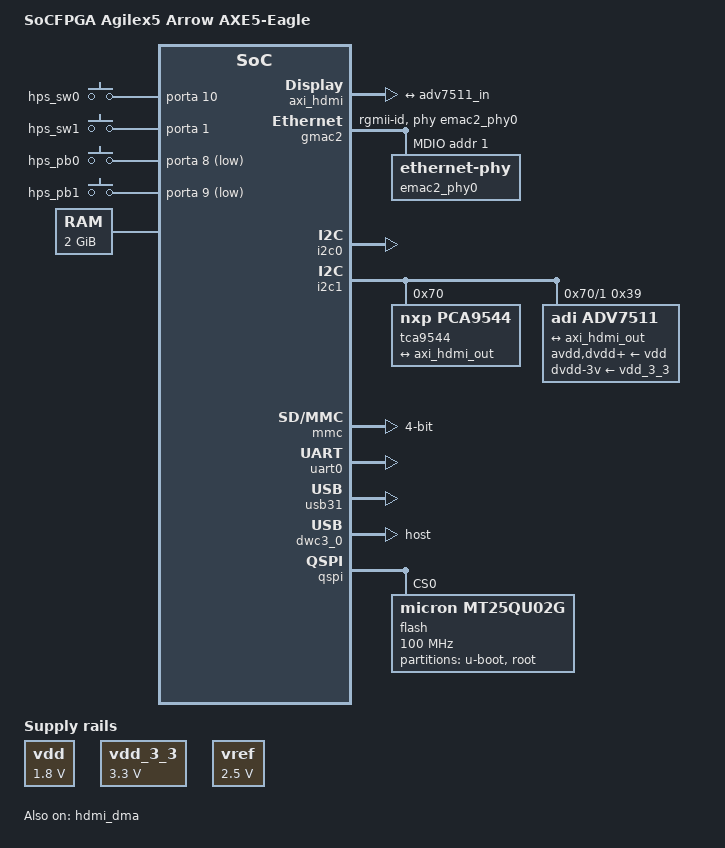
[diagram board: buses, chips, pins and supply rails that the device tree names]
// SPDX-License-Identifier:     GPL-2.0
/*
 * Copyright (C) 2024, Arrow Electronics, Inc.
 */
#include "../intel/socfpga_agilex5.dtsi"


/ {
	model = "SoCFPGA Agilex5 Arrow AXE5-Eagle";
	compatible = "intel,socfpga-agilex5-socdk", "intel,socfpga-agilex";

	aliases {
		serial0 = &uart0;
		ethernet0 = &gmac0;
		ethernet2 = &gmac2;
	};

	chosen {
		stdout-path = "serial0:115200n8";
		bootargs = "console=uart8250,mmio32,0x10c02000,115200n8 \
			root=/dev/ram0 rw initrd=0x10000000 init=/sbin/init \
			ramdisk_size=10000000 earlycon=uart8250,mmio32,0x10c02000,115200n8 \
			panic=-1 nosmp rootfstype=ext3";
	};

	/*leds {
		compatible = "gpio-leds";
		
		hps0 {
			label = "hps_led0";
			gpios = <&porta 6 GPIO_ACTIVE_HIGH>;
		};		

		hps1 {
			label = "hps_led1";
			gpios = <&porta 7 GPIO_ACTIVE_HIGH>;
		};
		
		fpga0_led_red {
			label = "fpga_led0_red";
			gpios = <&led_pio0 2 1>;
		};
		
		fpga0_led_green {
			label = "fpga_led0_green";
			gpios = <&led_pio0 1 1>;
		};	
		
		fpga0_led_blue {
			label = "fpga_led0_blue";
			gpios = <&led_pio0 0 1>;
		};
		
		fpga1_led_red {
			label = "fpga_led1_red";
			gpios = <&led_pio1 2 1>;
		};
		
		fpga1_led_green {
			label = "fpga_led1_green";
			gpios = <&led_pio1 1 1>;
		};	
		
		fpga1_led_blue {
			label = "fpga_led1_blue";
			gpios = <&led_pio1 0 1>;
		};
		
		fpga2_led_red {
			label = "fpga_led2_red";
			gpios = <&led_pio2 2 1>;
		};
		
		fpga2_led_green {
			label = "fpga_led2_green";
			gpios = <&led_pio2 1 1>;
		};	
		
		fpga2_led_blue {
			label = "fpga_led2_blue";
			gpios = <&led_pio2 0 1>;
		};
		
		fpga3_led_red {
			label = "fpga_led3_red";
			gpios = <&led_pio3 2 1>;
		};
		
		fpga3_led_green {
			label = "fpga_led3_green";
			gpios = <&led_pio3 1 1>;
		};	
		
		fpga3_led_blue {
			label = "fpga_led3_blue";
			gpios = <&led_pio3 0 1>;
		};									

	}; */
	
	gpio-keys {
		compatible = "gpio-keys";

		hps_sw0 {
			label = "hps_sw0";
			gpios = <&porta 10 0>;	
			linux,input-type = <5>;	/* EV_SW */
			linux,code = <0x0>;		
		};
		
		hps_sw1 {
			label = "hps_sw1";
			gpios = <&porta 1 0>;	
			linux,input-type = <5>;	/* EV_SW */
			linux,code = <0x0>;		
		};
		
		hps_pb0 {
			label = "hps_pb0";
			gpios = <&porta 8 1>;	
			linux,code = <187>;		/* KEY_F17 */
		};

		hps_pb1 {
			label = "hps_pb1";
			gpios = <&porta 9 1>;	
			linux,code = <188>;		/* KEY_F18 */
		};		
	};					

	memory {
		device_type = "memory";
		reg = <0x0 0x80000000 0x0 0x80000000>;
		#address-cells = <0x2>;
		#size-cells = <0x2>;
		u-boot,dm-pre-reloc;
	};
	
	dma_clk: dma_clk {
		#clock-cells = <0x0>;
		compatible = "fixed-clock";
		clock-frequency = <250000000>;
		clock-output-names = "dma_clock";
	};	
	
	hdmi_pll: hdmi_pll {
		compatible = "altr,altera_iopll-18.1";
		#clock-cells = <1>;
			hdmi_pll_outclk0: hdmi_pll_outclk0 {
			compatible = "fixed-clock";
			#clock-cells = <0>;
			clock-frequency = <148437500>;
			clock-output-names = "hdmi_pll-outclk0";
		}; 
	};
	
        vdd: regulator-vdd {
                compatible = "regulator-fixed";
                regulator-name = "fixed-supply";
                regulator-min-microvolt = <1800000>;
                regulator-max-microvolt = <1800000>;
                regulator-always-on;
        };

        vdd_3_3: regulator-vdd {
                compatible = "regulator-fixed";
                regulator-name = "fixed-supply";
                regulator-min-microvolt = <3300000>;
                regulator-max-microvolt = <3300000>;
                regulator-always-on;
        };

        vref: regulator-vref {
                compatible = "regulator-fixed";
                regulator-name = "fixed-supply";
                regulator-min-microvolt = <2500000>;
                regulator-max-microvolt = <2500000>;
                regulator-always-on;
        };		
	
	soc {
		sys_hps_bridges: bridge@20000000 {
			compatible = "simple-bus";
			reg = <0x20000000 0x20000000>;
			reg-names = "axi_h2f_lw";
			#address-cells = <2>;
			#size-cells = <1>;
			ranges = <0x00000001 0x08000000 0x28000000 0x00000008>,
				 <0x00000001 0x08000010 0x28000010 0x00000010>,
	  			 <0x00000001 0x08000020 0x28000020 0x00000010>,
	  			 <0x00000001 0x08000030 0x28000030 0x00000010>,
	  			 <0x00000001 0x08000040 0x28000040 0x00000010>,
	  			 <0x00000001 0x08000050 0x28000050 0x00000010>,
	  			 <0x00000001 0x08000060 0x28000060 0x00000010>,
				 <0x00000001 0x10000000 0x30000000 0x00010000>,
				 <0x00000001 0x10010000 0x30010000 0x00000800>;
				 
			sys_id: sys-id@108000000 {
				compatible = "altr,sysid-1.0";
				reg = <0x00000001 0x08000000 0x08>;
			};				 
				 
			/* pio device tree entry. for additional information see /linux/Documentation/devicetree/bindings/gpio/gpio-altera.txt */

			button_pio: button-pio@108000010 {
				compatible = "altr,pio-1.0";
				reg = <0x00000001 0x08000010 0x10>;
				interrupt-parent = <&intc>;
				interrupts = <0 20 4>;
				altr,ngpio = <2>;
				#gpio-cells = <2>;
				gpio-controller;
				interrupt-cells = <1>;
				interrupt-controller;
				altr,interrupt-type = <IRQ_TYPE_EDGE_FALLING>;
			};

			dipsw_pio: button-pio@108000020 {
				compatible = "altr,pio-1.0";
				reg = <0x00000001 0x08000020 0x10>;
				interrupt-parent = <&intc>;
				interrupts = <0 18 4>;
				altr,ngpio = <2>;
				#gpio-cells = <2>;
				gpio-controller;
				interrupt-cells = <1>;
				interrupt-controller;
				altr,interrupt-type = <IRQ_TYPE_EDGE_BOTH>;
			};

			led_pio0: led-pio0@108000030 {
				compatible = "altr,pio-1.0";
				reg = <0x00000001 0x08000030 0x10>;
				altr,ngpio = <3>;
				#gpio-cells = <2>;
				gpio-controller;
			};
			
			led_pio1: led-pio1@108000040 {
				compatible = "altr,pio-1.0";
				reg = <0x00000001 0x08000040 0x10>;
				altr,ngpio = <3>;
				#gpio-cells = <2>;
				gpio-controller;
			};
			
			led_pio2: led-pio2@108000050 {
				compatible = "altr,pio-1.0";
				reg = <0x00000001 0x01000050 0x10>;
				altr,ngpio = <3>;
				#gpio-cells = <2>;
				gpio-controller;
			};
			
			led_pio3: led-pio3@108000060 {
				compatible = "altr,pio-1.0";
				reg = <0x00000001 0x01000060 0x10>;
				altr,ngpio = <3>;
				#gpio-cells = <2>;
				gpio-controller;
			};									


			hdmi_dma: hdmi-dma@110010000 {
				compatible = "adi,axi-dmac-1.00.a";
				reg = <0x00000001 0x10010000 0x0800>;
				#dma-cells = <1>;
				interrupt-parent = <&intc>;
				interrupts = <0 21 4>;
				clocks = <&dma_clk 0>;
				status = "okay";

				adi,channels {
					#size-cells = <0>;
					#address-cells = <1>;

					dma-channel@0 {
						reg = <0>;
						adi,source-bus-width = <256>;
						adi,source-bus-type = <0>;
						adi,destination-bus-width = <64>;
						adi,destination-bus-type = <1>;
					};
				};
			};


			axi_hdmi: axi-hdmi@110000000 {
				compatible = "adi,axi-hdmi-tx-1.00.a";
				reg = <0x00000001 0x10000000 0x10000>;
				dmas = <&hdmi_dma 0>;
				dma-names = "video";
				clocks = <&hdmi_pll 0>;
				status = "okay";
	
				port {
					axi_hdmi_out: endpoint {
						remote-endpoint = <&adv7511_in>;
					};
				};
			};
		};				 
	};
};

&gpio0 {
	status = "okay";
};

&gmac0 {
	status = "disabled";
	phy-mode = "rgmii-id";
	phy-handle = <&emac0_phy0>;

	max-frame-size = <9000>;

	mdio0 {
		#address-cells = <1>;
		#size-cells = <0>;
		compatible = "snps,dwmac-mdio";
		emac0_phy0: ethernet-phy@1 {
			reg = <1>;
			adi,rx-internal-delay-ps = <2000>;
			adi,tx-internal-delay-ps = <2000>;			
		};
	};
};

&gmac2 {
	status = "okay";
	phy-mode = "rgmii-id";
	phy-handle = <&emac2_phy0>;

	max-frame-size = <9000>;

	mdio0 {
		#address-cells = <1>;
		#size-cells = <0>;
		compatible = "snps,dwmac-mdio";
		emac2_phy0: ethernet-phy@1 {
			reg = <1>;
			adi,rx-internal-delay-ps = <2000>;
			adi,tx-internal-delay-ps = <2000>;
		};
	};
};

&i2c0 {
	status = "okay";
};

&i2c1 {
	status = "okay";

	tca9544@70 {
		compatible = "nxp,pca9544";
    		#address-cells = <1>;
    		#size-cells = <0>;
    		reg = <0x70>;
    		status = "okay";
    		i2c@1 { 
			#address-cells = <1>;
			#size-cells = <0>;
			reg = <1>;
			adv7511: adv7511@39 {
				compatible = "adi,adv7511";
				reg = <0x39>, <0x3f>;
				reg-names = "primary", "edid";

				adi,input-depth = <8>;
				adi,input-colorspace = "yuv422";
				adi,input-clock = "1x";
				adi,input-style = <1>;
				adi,input-justification = "right";
				adi,clock-delay = <(0)>;

				avdd-supply = <&vdd>;
				dvdd-supply = <&vdd>;
				pvdd-supply = <&vdd>;
				dvdd-3v-supply = <&vdd_3_3>;
				bgvdd-supply = <&vdd>;

				status = "okay";
				
				ports {
					#address-cells = <1>;
					#size-cells = <0>;

					port@0 {
						reg = <0>;
						adv7511_in: endpoint {
							remote-endpoint = <&axi_hdmi_out>;
						};
					}; 

					port@1 {
						reg = <1>;
						
					};

				};				
			};
		};
    		
    	};	
};    		
    		

&mmc {
	status = "okay";
	bus-width = <4>;
	disable-wp;
	no-1-8-v;
	cap-sd-highspeed;
	sd-uhs-sdr50;
	sdhci-caps = <0x00000000 0x0000c800>;
	sdhci-caps-mask = <0x00002000 0x0000ff00>;
	no-sdio;
	cdns,phy-use-ext-lpbk-dqs = <1>;
	cdns,phy-use-lpbk-dqs = <1>;
	cdns,phy-use-phony-dqs = <1>;
	cdns,phy-use-phony-dqs-cmd = <1>;
	cdns,phy-io-mask-always-on = <0>;
	cdns,phy-io-mask-end = <5>;
	cdns,phy-io-mask-start = <0>;
	cdns,phy-data-select-oe-end = <1>;
	cdns,phy-sync-method = <1>;
	cdns,phy-sw-half-cycle-shift = <0>;
	cdns,phy-rd-del-sel = <52>;
	cdns,phy-underrun-suppress = <1>;
	cdns,phy-gate-cfg-always-on = <1>;
	cdns,phy-param-dll-bypass-mode = <1>;
	cdns,phy-param-phase-detect-sel = <2>;
	cdns,phy-param-dll-start-point = <254>;
	cdns,phy-read-dqs-cmd-delay = <0>;
	cdns,phy-clk-wrdqs-delay = <0>;
	cdns,phy-clk-wr-delay = <0>;
	cdns,phy-read-dqs-delay = <0>;
	cdns,phy-phony-dqs-timing = <0>;
	cdns,hrs09-rddata-en = <1>;
	cdns,hrs09-rdcmd-en = <1>;
	cdns,hrs09-extended-wr-mode = <1>;
	cdns,hrs09-extended-rd-mode = <1>;
	cdns,hrs10-hcsdclkadj = <3>;
	cdns,hrs16-wrdata1-sdclk-dly = <0>;
	cdns,hrs16-wrdata0-sdclk-dly = <0>;
	cdns,hrs16-wrcmd1-sdclk-dly = <0>;
	cdns,hrs16-wrcmd0-sdclk-dly = <0>;
	cdns,hrs16-wrdata1-dly = <0>;
	cdns,hrs16-wrdata0-dly = <0>;
	cdns,hrs16-wrcmd1-dly = <0>;
	cdns,hrs16-wrcmd0-dly = <0>;
	cdns,hrs07-rw-compensate = <10>;
	cdns,hrs07-idelay-val = <0>;
};

&osc1 {
	clock-frequency = <25000000>;
};

&uart0 {
	status = "okay";
};

&usb0 {
	status = "disabled";
	disable-over-current;
};

&usb31 {
	status = "okay";
};

&dwc3_0 {
	dr_mode = "host";
};

&smmu {
	status = "okay";
};

&watchdog0 {
	status = "disabled";
};
&watchdog1 {
	status = "disabled";
};
&watchdog2 {
	status = "disabled";
};
&watchdog3 {
	status = "disabled";
};
&watchdog4 {
	status = "disabled";
};

&qspi {
	status = "okay";
	flash@0 {
		#address-cells = <1>;
		#size-cells = <1>;
		compatible = "micron,mt25qu02g", "jedec,spi-nor";
		reg = <0>;
		spi-max-frequency = <100000000>;

		m25p,fast-read;
		cdns,page-size = <256>;
		cdns,block-size = <16>;
		cdns,read-delay = <2>;
		cdns,tshsl-ns = <50>;
		cdns,tsd2d-ns = <50>;
		cdns,tchsh-ns = <4>;
		cdns,tslch-ns = <4>;

		partitions {
			compatible = "fixed-partitions";
			#address-cells = <1>;
			#size-cells = <1>;
			rsu-handle = <&qspi_boot>;

			qspi_boot: partition@0 {
				label = "u-boot";
				reg = <0x0 0x04200000>;
			};

			root: partition@4200000 {
				label = "root";
				reg = <0x04200000 0x0BE00000>;
			};
		};
	};
};

